VERSION 5.7 ;
  NOWIREEXTENSIONATPIN ON ;
  DIVIDERCHAR "/" ;
  BUSBITCHARS "[]" ;
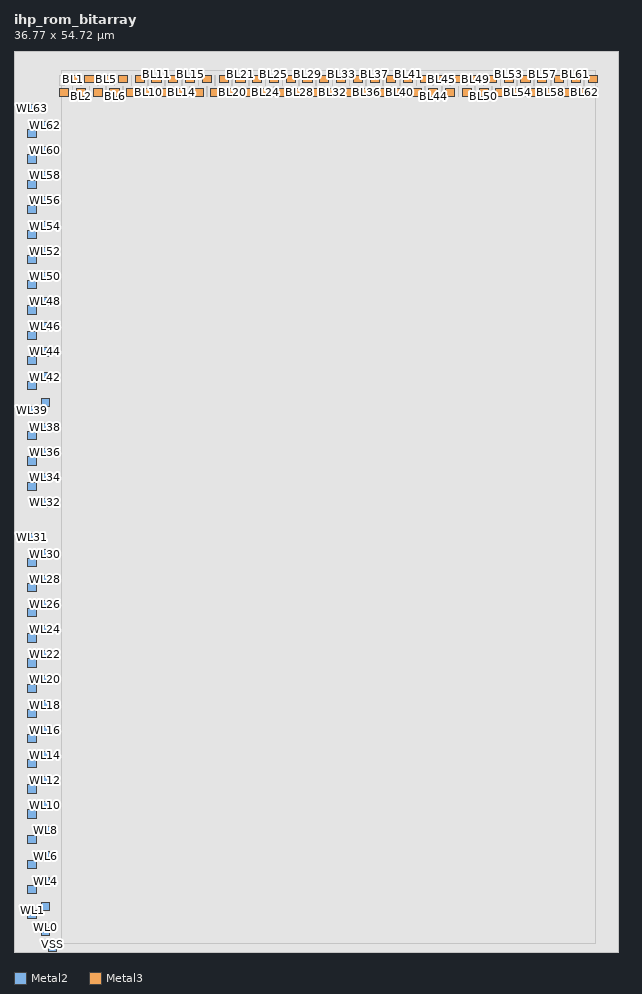
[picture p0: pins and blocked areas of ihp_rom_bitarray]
MACRO ihp_rom_bitarray
  CLASS BLOCK ;
  FOREIGN ihp_rom_bitarray ;
  ORIGIN 2.800 0.990 ;
  SIZE 36.770 BY 54.720 ;
  PIN VSS
    USE GROUND ;
    PORT
      LAYER Metal2 ;
        RECT -0.700 -0.970 -0.200 -0.610 ;
    END
  END VSS
  PIN WL0
    ANTENNAGATEAREA 2.496000 ;
    PORT
      LAYER Metal2 ;
        RECT -1.150 0.005 -0.650 0.505 ;
    END
  END WL0
  PIN WL1
    ANTENNAGATEAREA 2.496000 ;
    PORT
      LAYER Metal2 ;
        RECT -1.950 1.025 -1.450 1.525 ;
    END
  END WL1
  PIN WL2
    ANTENNAGATEAREA 2.496000 ;
    PORT
      LAYER Metal2 ;
        RECT -1.150 1.535 -0.650 2.035 ;
    END
  END WL2
  PIN WL3
    ANTENNAGATEAREA 2.496000 ;
    PORT
      LAYER Metal2 ;
        RECT -1.950 2.555 -1.450 3.055 ;
    END
  END WL3
  PIN WL4
    ANTENNAGATEAREA 2.496000 ;
    PORT
      LAYER Metal2 ;
        RECT -1.150 3.065 -0.650 3.565 ;
    END
  END WL4
  PIN WL5
    ANTENNAGATEAREA 2.496000 ;
    PORT
      LAYER Metal2 ;
        RECT -1.950 4.085 -1.450 4.585 ;
    END
  END WL5
  PIN WL6
    ANTENNAGATEAREA 2.496000 ;
    PORT
      LAYER Metal2 ;
        RECT -1.150 4.595 -0.650 5.095 ;
    END
  END WL6
  PIN WL7
    ANTENNAGATEAREA 2.496000 ;
    PORT
      LAYER Metal2 ;
        RECT -1.950 5.615 -1.450 6.115 ;
    END
  END WL7
  PIN WL8
    ANTENNAGATEAREA 2.496000 ;
    PORT
      LAYER Metal2 ;
        RECT -1.150 6.125 -0.650 6.625 ;
    END
  END WL8
  PIN WL9
    ANTENNAGATEAREA 2.496000 ;
    PORT
      LAYER Metal2 ;
        RECT -1.950 7.145 -1.450 7.645 ;
    END
  END WL9
  PIN WL10
    ANTENNAGATEAREA 2.496000 ;
    PORT
      LAYER Metal2 ;
        RECT -1.150 7.655 -0.650 8.155 ;
    END
  END WL10
  PIN WL11
    ANTENNAGATEAREA 2.496000 ;
    PORT
      LAYER Metal2 ;
        RECT -1.950 8.675 -1.450 9.175 ;
    END
  END WL11
  PIN WL12
    ANTENNAGATEAREA 2.496000 ;
    PORT
      LAYER Metal2 ;
        RECT -1.150 9.185 -0.650 9.685 ;
    END
  END WL12
  PIN WL13
    ANTENNAGATEAREA 2.496000 ;
    PORT
      LAYER Metal2 ;
        RECT -1.950 10.205 -1.450 10.705 ;
    END
  END WL13
  PIN WL14
    ANTENNAGATEAREA 2.496000 ;
    PORT
      LAYER Metal2 ;
        RECT -1.150 10.715 -0.650 11.215 ;
    END
  END WL14
  PIN WL15
    ANTENNAGATEAREA 2.496000 ;
    PORT
      LAYER Metal2 ;
        RECT -1.950 11.735 -1.450 12.235 ;
    END
  END WL15
  PIN WL16
    ANTENNAGATEAREA 2.496000 ;
    PORT
      LAYER Metal2 ;
        RECT -1.150 12.245 -0.650 12.745 ;
    END
  END WL16
  PIN WL17
    ANTENNAGATEAREA 2.496000 ;
    PORT
      LAYER Metal2 ;
        RECT -1.950 13.265 -1.450 13.765 ;
    END
  END WL17
  PIN WL18
    ANTENNAGATEAREA 2.496000 ;
    PORT
      LAYER Metal2 ;
        RECT -1.150 13.775 -0.650 14.275 ;
    END
  END WL18
  PIN WL19
    ANTENNAGATEAREA 2.496000 ;
    PORT
      LAYER Metal2 ;
        RECT -1.950 14.795 -1.450 15.295 ;
    END
  END WL19
  PIN WL20
    ANTENNAGATEAREA 2.496000 ;
    PORT
      LAYER Metal2 ;
        RECT -1.150 15.305 -0.650 15.805 ;
    END
  END WL20
  PIN WL21
    ANTENNAGATEAREA 2.496000 ;
    PORT
      LAYER Metal2 ;
        RECT -1.950 16.325 -1.450 16.825 ;
    END
  END WL21
  PIN WL22
    ANTENNAGATEAREA 2.496000 ;
    PORT
      LAYER Metal2 ;
        RECT -1.150 16.835 -0.650 17.335 ;
    END
  END WL22
  PIN WL23
    ANTENNAGATEAREA 2.496000 ;
    PORT
      LAYER Metal2 ;
        RECT -1.950 17.855 -1.450 18.355 ;
    END
  END WL23
  PIN WL24
    ANTENNAGATEAREA 2.496000 ;
    PORT
      LAYER Metal2 ;
        RECT -1.150 18.365 -0.650 18.865 ;
    END
  END WL24
  PIN WL25
    ANTENNAGATEAREA 2.496000 ;
    PORT
      LAYER Metal2 ;
        RECT -1.950 19.385 -1.450 19.885 ;
    END
  END WL25
  PIN WL26
    ANTENNAGATEAREA 2.496000 ;
    PORT
      LAYER Metal2 ;
        RECT -1.150 19.895 -0.650 20.395 ;
    END
  END WL26
  PIN WL27
    ANTENNAGATEAREA 2.496000 ;
    PORT
      LAYER Metal2 ;
        RECT -1.950 20.915 -1.450 21.415 ;
    END
  END WL27
  PIN WL28
    ANTENNAGATEAREA 2.496000 ;
    PORT
      LAYER Metal2 ;
        RECT -1.150 21.425 -0.650 21.925 ;
    END
  END WL28
  PIN WL29
    ANTENNAGATEAREA 2.496000 ;
    PORT
      LAYER Metal2 ;
        RECT -1.950 22.445 -1.450 22.945 ;
    END
  END WL29
  PIN WL30
    ANTENNAGATEAREA 2.496000 ;
    PORT
      LAYER Metal2 ;
        RECT -1.150 22.955 -0.650 23.455 ;
    END
  END WL30
  PIN WL31
    ANTENNAGATEAREA 2.496000 ;
    PORT
      LAYER Metal2 ;
        RECT -1.950 23.975 -1.450 24.475 ;
    END
  END WL31
  PIN WL32
    ANTENNAGATEAREA 2.496000 ;
    PORT
      LAYER Metal2 ;
        RECT -1.150 26.065 -0.650 26.565 ;
    END
  END WL32
  PIN WL33
    ANTENNAGATEAREA 2.496000 ;
    PORT
      LAYER Metal2 ;
        RECT -1.950 27.085 -1.450 27.585 ;
    END
  END WL33
  PIN WL34
    ANTENNAGATEAREA 2.496000 ;
    PORT
      LAYER Metal2 ;
        RECT -1.150 27.595 -0.650 28.095 ;
    END
  END WL34
  PIN WL35
    ANTENNAGATEAREA 2.496000 ;
    PORT
      LAYER Metal2 ;
        RECT -1.950 28.615 -1.450 29.115 ;
    END
  END WL35
  PIN WL36
    ANTENNAGATEAREA 2.496000 ;
    PORT
      LAYER Metal2 ;
        RECT -1.150 29.125 -0.650 29.625 ;
    END
  END WL36
  PIN WL37
    ANTENNAGATEAREA 2.496000 ;
    PORT
      LAYER Metal2 ;
        RECT -1.950 30.145 -1.450 30.645 ;
    END
  END WL37
  PIN WL38
    ANTENNAGATEAREA 2.496000 ;
    PORT
      LAYER Metal2 ;
        RECT -1.150 30.655 -0.650 31.155 ;
    END
  END WL38
  PIN WL39
    ANTENNAGATEAREA 2.496000 ;
    PORT
      LAYER Metal2 ;
        RECT -1.950 31.675 -1.450 32.175 ;
    END
  END WL39
  PIN WL40
    ANTENNAGATEAREA 2.496000 ;
    PORT
      LAYER Metal2 ;
        RECT -1.150 32.185 -0.650 32.685 ;
    END
  END WL40
  PIN WL41
    ANTENNAGATEAREA 2.496000 ;
    PORT
      LAYER Metal2 ;
        RECT -1.950 33.205 -1.450 33.705 ;
    END
  END WL41
  PIN WL42
    ANTENNAGATEAREA 2.496000 ;
    PORT
      LAYER Metal2 ;
        RECT -1.150 33.715 -0.650 34.215 ;
    END
  END WL42
  PIN WL43
    ANTENNAGATEAREA 2.496000 ;
    PORT
      LAYER Metal2 ;
        RECT -1.950 34.735 -1.450 35.235 ;
    END
  END WL43
  PIN WL44
    ANTENNAGATEAREA 2.496000 ;
    PORT
      LAYER Metal2 ;
        RECT -1.150 35.245 -0.650 35.745 ;
    END
  END WL44
  PIN WL45
    ANTENNAGATEAREA 2.496000 ;
    PORT
      LAYER Metal2 ;
        RECT -1.950 36.265 -1.450 36.765 ;
    END
  END WL45
  PIN WL46
    ANTENNAGATEAREA 2.496000 ;
    PORT
      LAYER Metal2 ;
        RECT -1.150 36.775 -0.650 37.275 ;
    END
  END WL46
  PIN WL47
    ANTENNAGATEAREA 2.496000 ;
    PORT
      LAYER Metal2 ;
        RECT -1.950 37.795 -1.450 38.295 ;
    END
  END WL47
  PIN WL48
    ANTENNAGATEAREA 2.496000 ;
    PORT
      LAYER Metal2 ;
        RECT -1.150 38.305 -0.650 38.805 ;
    END
  END WL48
  PIN WL49
    ANTENNAGATEAREA 2.496000 ;
    PORT
      LAYER Metal2 ;
        RECT -1.950 39.325 -1.450 39.825 ;
    END
  END WL49
  PIN WL50
    ANTENNAGATEAREA 2.496000 ;
    PORT
      LAYER Metal2 ;
        RECT -1.150 39.835 -0.650 40.335 ;
    END
  END WL50
  PIN WL51
    ANTENNAGATEAREA 2.496000 ;
    PORT
      LAYER Metal2 ;
        RECT -1.950 40.855 -1.450 41.355 ;
    END
  END WL51
  PIN WL52
    ANTENNAGATEAREA 2.496000 ;
    PORT
      LAYER Metal2 ;
        RECT -1.150 41.365 -0.650 41.865 ;
    END
  END WL52
  PIN WL53
    ANTENNAGATEAREA 2.496000 ;
    PORT
      LAYER Metal2 ;
        RECT -1.950 42.385 -1.450 42.885 ;
    END
  END WL53
  PIN WL54
    ANTENNAGATEAREA 2.496000 ;
    PORT
      LAYER Metal2 ;
        RECT -1.150 42.895 -0.650 43.395 ;
    END
  END WL54
  PIN WL55
    ANTENNAGATEAREA 2.496000 ;
    PORT
      LAYER Metal2 ;
        RECT -1.950 43.915 -1.450 44.415 ;
    END
  END WL55
  PIN WL56
    ANTENNAGATEAREA 2.496000 ;
    PORT
      LAYER Metal2 ;
        RECT -1.150 44.425 -0.650 44.925 ;
    END
  END WL56
  PIN WL57
    ANTENNAGATEAREA 2.496000 ;
    PORT
      LAYER Metal2 ;
        RECT -1.950 45.445 -1.450 45.945 ;
    END
  END WL57
  PIN WL58
    ANTENNAGATEAREA 2.496000 ;
    PORT
      LAYER Metal2 ;
        RECT -1.150 45.955 -0.650 46.455 ;
    END
  END WL58
  PIN WL59
    ANTENNAGATEAREA 2.496000 ;
    PORT
      LAYER Metal2 ;
        RECT -1.950 46.975 -1.450 47.475 ;
    END
  END WL59
  PIN WL60
    ANTENNAGATEAREA 2.496000 ;
    PORT
      LAYER Metal2 ;
        RECT -1.150 47.485 -0.650 47.985 ;
    END
  END WL60
  PIN WL61
    ANTENNAGATEAREA 2.496000 ;
    PORT
      LAYER Metal2 ;
        RECT -1.950 48.505 -1.450 49.005 ;
    END
  END WL61
  PIN WL62
    ANTENNAGATEAREA 2.496000 ;
    PORT
      LAYER Metal2 ;
        RECT -1.150 49.015 -0.650 49.515 ;
    END
  END WL62
  PIN WL63
    ANTENNAGATEAREA 2.496000 ;
    PORT
      LAYER Metal2 ;
        RECT -1.950 50.035 -1.450 50.535 ;
    END
  END WL63
  PIN BL0
    ANTENNADIFFAREA 3.468000 ;
    PORT
      LAYER Metal3 ;
        RECT -0.025 51.050 0.535 51.510 ;
    END
  END BL0
  PIN BL1
    ANTENNADIFFAREA 3.060000 ;
    PORT
      LAYER Metal3 ;
        RECT 0.485 51.850 1.045 52.310 ;
    END
  END BL1
  PIN BL2
    ANTENNADIFFAREA 3.060000 ;
    PORT
      LAYER Metal3 ;
        RECT 0.995 51.050 1.555 51.510 ;
    END
  END BL2
  PIN BL3
    ANTENNADIFFAREA 3.468000 ;
    PORT
      LAYER Metal3 ;
        RECT 1.505 51.850 2.065 52.310 ;
    END
  END BL3
  PIN BL4
    ANTENNADIFFAREA 3.060000 ;
    PORT
      LAYER Metal3 ;
        RECT 2.015 51.050 2.575 51.510 ;
    END
  END BL4
  PIN BL5
    ANTENNADIFFAREA 3.060000 ;
    PORT
      LAYER Metal3 ;
        RECT 2.525 51.850 3.085 52.310 ;
    END
  END BL5
  PIN BL6
    ANTENNADIFFAREA 3.468000 ;
    PORT
      LAYER Metal3 ;
        RECT 3.035 51.050 3.595 51.510 ;
    END
  END BL6
  PIN BL7
    ANTENNADIFFAREA 3.060000 ;
    PORT
      LAYER Metal3 ;
        RECT 3.545 51.850 4.105 52.310 ;
    END
  END BL7
  PIN BL8
    ANTENNADIFFAREA 3.060000 ;
    PORT
      LAYER Metal3 ;
        RECT 4.055 51.050 4.615 51.510 ;
    END
  END BL8
  PIN BL9
    ANTENNADIFFAREA 3.468000 ;
    PORT
      LAYER Metal3 ;
        RECT 4.565 51.850 5.125 52.310 ;
    END
  END BL9
  PIN BL10
    ANTENNADIFFAREA 3.468000 ;
    PORT
      LAYER Metal3 ;
        RECT 5.075 51.050 5.635 51.510 ;
    END
  END BL10
  PIN BL11
    ANTENNADIFFAREA 3.060000 ;
    PORT
      LAYER Metal3 ;
        RECT 5.585 51.850 6.145 52.310 ;
    END
  END BL11
  PIN BL12
    ANTENNADIFFAREA 3.468000 ;
    PORT
      LAYER Metal3 ;
        RECT 6.095 51.050 6.655 51.510 ;
    END
  END BL12
  PIN BL13
    ANTENNADIFFAREA 3.468000 ;
    PORT
      LAYER Metal3 ;
        RECT 6.605 51.850 7.165 52.310 ;
    END
  END BL13
  PIN BL14
    ANTENNADIFFAREA 3.060000 ;
    PORT
      LAYER Metal3 ;
        RECT 7.115 51.050 7.675 51.510 ;
    END
  END BL14
  PIN BL15
    ANTENNADIFFAREA 3.468000 ;
    PORT
      LAYER Metal3 ;
        RECT 7.625 51.850 8.185 52.310 ;
    END
  END BL15
  PIN BL16
    ANTENNADIFFAREA 3.060000 ;
    PORT
      LAYER Metal3 ;
        RECT 8.135 51.050 8.695 51.510 ;
    END
  END BL16
  PIN BL17
    ANTENNADIFFAREA 3.468000 ;
    PORT
      LAYER Metal3 ;
        RECT 8.645 51.850 9.205 52.310 ;
    END
  END BL17
  PIN BL18
    ANTENNADIFFAREA 3.468000 ;
    PORT
      LAYER Metal3 ;
        RECT 9.155 51.050 9.715 51.510 ;
    END
  END BL18
  PIN BL19
    ANTENNADIFFAREA 3.060000 ;
    PORT
      LAYER Metal3 ;
        RECT 9.665 51.850 10.225 52.310 ;
    END
  END BL19
  PIN BL20
    ANTENNADIFFAREA 3.468000 ;
    PORT
      LAYER Metal3 ;
        RECT 10.175 51.050 10.735 51.510 ;
    END
  END BL20
  PIN BL21
    ANTENNADIFFAREA 3.468000 ;
    PORT
      LAYER Metal3 ;
        RECT 10.685 51.850 11.245 52.310 ;
    END
  END BL21
  PIN BL22
    ANTENNADIFFAREA 3.060000 ;
    PORT
      LAYER Metal3 ;
        RECT 11.195 51.050 11.755 51.510 ;
    END
  END BL22
  PIN BL23
    ANTENNADIFFAREA 3.468000 ;
    PORT
      LAYER Metal3 ;
        RECT 11.705 51.850 12.265 52.310 ;
    END
  END BL23
  PIN BL24
    ANTENNADIFFAREA 3.468000 ;
    PORT
      LAYER Metal3 ;
        RECT 12.215 51.050 12.775 51.510 ;
    END
  END BL24
  PIN BL25
    ANTENNADIFFAREA 3.060000 ;
    PORT
      LAYER Metal3 ;
        RECT 12.725 51.850 13.285 52.310 ;
    END
  END BL25
  PIN BL26
    ANTENNADIFFAREA 3.060000 ;
    PORT
      LAYER Metal3 ;
        RECT 13.235 51.050 13.795 51.510 ;
    END
  END BL26
  PIN BL27
    ANTENNADIFFAREA 3.468000 ;
    PORT
      LAYER Metal3 ;
        RECT 13.745 51.850 14.305 52.310 ;
    END
  END BL27
  PIN BL28
    ANTENNADIFFAREA 3.060000 ;
    PORT
      LAYER Metal3 ;
        RECT 14.255 51.050 14.815 51.510 ;
    END
  END BL28
  PIN BL29
    ANTENNADIFFAREA 3.060000 ;
    PORT
      LAYER Metal3 ;
        RECT 14.765 51.850 15.325 52.310 ;
    END
  END BL29
  PIN BL30
    ANTENNADIFFAREA 3.468000 ;
    PORT
      LAYER Metal3 ;
        RECT 15.275 51.050 15.835 51.510 ;
    END
  END BL30
  PIN BL31
    ANTENNADIFFAREA 3.060000 ;
    PORT
      LAYER Metal3 ;
        RECT 15.785 51.850 16.345 52.310 ;
    END
  END BL31
  PIN BL32
    ANTENNADIFFAREA 3.468000 ;
    PORT
      LAYER Metal3 ;
        RECT 16.295 51.050 16.855 51.510 ;
    END
  END BL32
  PIN BL33
    ANTENNADIFFAREA 3.060000 ;
    PORT
      LAYER Metal3 ;
        RECT 16.805 51.850 17.365 52.310 ;
    END
  END BL33
  PIN BL34
    ANTENNADIFFAREA 3.060000 ;
    PORT
      LAYER Metal3 ;
        RECT 17.315 51.050 17.875 51.510 ;
    END
  END BL34
  PIN BL35
    ANTENNADIFFAREA 3.468000 ;
    PORT
      LAYER Metal3 ;
        RECT 17.825 51.850 18.385 52.310 ;
    END
  END BL35
  PIN BL36
    ANTENNADIFFAREA 3.060000 ;
    PORT
      LAYER Metal3 ;
        RECT 18.335 51.050 18.895 51.510 ;
    END
  END BL36
  PIN BL37
    ANTENNADIFFAREA 3.060000 ;
    PORT
      LAYER Metal3 ;
        RECT 18.845 51.850 19.405 52.310 ;
    END
  END BL37
  PIN BL38
    ANTENNADIFFAREA 3.468000 ;
    PORT
      LAYER Metal3 ;
        RECT 19.355 51.050 19.915 51.510 ;
    END
  END BL38
  PIN BL39
    ANTENNADIFFAREA 3.060000 ;
    PORT
      LAYER Metal3 ;
        RECT 19.865 51.850 20.425 52.310 ;
    END
  END BL39
  PIN BL40
    ANTENNADIFFAREA 3.060000 ;
    PORT
      LAYER Metal3 ;
        RECT 20.375 51.050 20.935 51.510 ;
    END
  END BL40
  PIN BL41
    ANTENNADIFFAREA 3.468000 ;
    PORT
      LAYER Metal3 ;
        RECT 20.885 51.850 21.445 52.310 ;
    END
  END BL41
  PIN BL42
    ANTENNADIFFAREA 3.468000 ;
    PORT
      LAYER Metal3 ;
        RECT 21.395 51.050 21.955 51.510 ;
    END
  END BL42
  PIN BL43
    ANTENNADIFFAREA 3.060000 ;
    PORT
      LAYER Metal3 ;
        RECT 21.905 51.850 22.465 52.310 ;
    END
  END BL43
  PIN BL44
    ANTENNADIFFAREA 3.468000 ;
    PORT
      LAYER Metal3 ;
        RECT 22.415 51.050 22.975 51.510 ;
    END
  END BL44
  PIN BL45
    ANTENNADIFFAREA 3.468000 ;
    PORT
      LAYER Metal3 ;
        RECT 22.925 51.850 23.485 52.310 ;
    END
  END BL45
  PIN BL46
    ANTENNADIFFAREA 3.060000 ;
    PORT
      LAYER Metal3 ;
        RECT 23.435 51.050 23.995 51.510 ;
    END
  END BL46
  PIN BL47
    ANTENNADIFFAREA 3.468000 ;
    PORT
      LAYER Metal3 ;
        RECT 23.945 51.850 24.505 52.310 ;
    END
  END BL47
  PIN BL48
    ANTENNADIFFAREA 3.060000 ;
    PORT
      LAYER Metal3 ;
        RECT 24.455 51.050 25.015 51.510 ;
    END
  END BL48
  PIN BL49
    ANTENNADIFFAREA 3.468000 ;
    PORT
      LAYER Metal3 ;
        RECT 24.965 51.850 25.525 52.310 ;
    END
  END BL49
  PIN BL50
    ANTENNADIFFAREA 3.468000 ;
    PORT
      LAYER Metal3 ;
        RECT 25.475 51.050 26.035 51.510 ;
    END
  END BL50
  PIN BL51
    ANTENNADIFFAREA 3.060000 ;
    PORT
      LAYER Metal3 ;
        RECT 25.985 51.850 26.545 52.310 ;
    END
  END BL51
  PIN BL52
    ANTENNADIFFAREA 3.468000 ;
    PORT
      LAYER Metal3 ;
        RECT 26.495 51.050 27.055 51.510 ;
    END
  END BL52
  PIN BL53
    ANTENNADIFFAREA 3.468000 ;
    PORT
      LAYER Metal3 ;
        RECT 27.005 51.850 27.565 52.310 ;
    END
  END BL53
  PIN BL54
    ANTENNADIFFAREA 3.060000 ;
    PORT
      LAYER Metal3 ;
        RECT 27.515 51.050 28.075 51.510 ;
    END
  END BL54
  PIN BL55
    ANTENNADIFFAREA 3.468000 ;
    PORT
      LAYER Metal3 ;
        RECT 28.025 51.850 28.585 52.310 ;
    END
  END BL55
  PIN BL56
    ANTENNADIFFAREA 3.468000 ;
    PORT
      LAYER Metal3 ;
        RECT 28.535 51.050 29.095 51.510 ;
    END
  END BL56
  PIN BL57
    ANTENNADIFFAREA 3.060000 ;
    PORT
      LAYER Metal3 ;
        RECT 29.045 51.850 29.605 52.310 ;
    END
  END BL57
  PIN BL58
    ANTENNADIFFAREA 3.060000 ;
    PORT
      LAYER Metal3 ;
        RECT 29.555 51.050 30.115 51.510 ;
    END
  END BL58
  PIN BL59
    ANTENNADIFFAREA 3.468000 ;
    PORT
      LAYER Metal3 ;
        RECT 30.065 51.850 30.625 52.310 ;
    END
  END BL59
  PIN BL60
    ANTENNADIFFAREA 3.060000 ;
    PORT
      LAYER Metal3 ;
        RECT 30.575 51.050 31.135 51.510 ;
    END
  END BL60
  PIN BL61
    ANTENNADIFFAREA 3.060000 ;
    PORT
      LAYER Metal3 ;
        RECT 31.085 51.850 31.645 52.310 ;
    END
  END BL61
  PIN BL62
    ANTENNADIFFAREA 3.468000 ;
    PORT
      LAYER Metal3 ;
        RECT 31.595 51.050 32.155 51.510 ;
    END
  END BL62
  PIN BL63
    ANTENNADIFFAREA 3.060000 ;
    PORT
      LAYER Metal3 ;
        RECT 32.105 51.850 32.665 52.310 ;
    END
  END BL63
  OBS
      LAYER GatPoly ;
        RECT -2.800 -0.990 33.970 53.730 ;
      LAYER Metal1 ;
        RECT -2.800 -0.990 33.970 53.730 ;
      LAYER Metal2 ;
        RECT 0.105 -0.490 32.535 52.630 ;
      LAYER Metal3 ;
        RECT -0.045 51.720 0.275 52.330 ;
        RECT 1.255 51.720 1.295 52.330 ;
        RECT 2.275 51.720 2.315 52.330 ;
        RECT 3.295 51.720 3.335 52.330 ;
        RECT 4.315 51.720 4.355 52.330 ;
        RECT 5.335 51.720 5.375 52.330 ;
        RECT 6.355 51.720 6.395 52.330 ;
        RECT 7.375 51.720 7.415 52.330 ;
        RECT 8.395 51.720 8.435 52.330 ;
        RECT 9.415 51.720 9.455 52.330 ;
        RECT 10.435 51.720 10.475 52.330 ;
        RECT 11.455 51.720 11.495 52.330 ;
        RECT 12.475 51.720 12.515 52.330 ;
        RECT 13.495 51.720 13.535 52.330 ;
        RECT 14.515 51.720 14.555 52.330 ;
        RECT 15.535 51.720 15.575 52.330 ;
        RECT 16.555 51.720 16.595 52.330 ;
        RECT 17.575 51.720 17.615 52.330 ;
        RECT 18.595 51.720 18.635 52.330 ;
        RECT 19.615 51.720 19.655 52.330 ;
        RECT 20.635 51.720 20.675 52.330 ;
        RECT 21.655 51.720 21.695 52.330 ;
        RECT 22.675 51.720 22.715 52.330 ;
        RECT 23.695 51.720 23.735 52.330 ;
        RECT 24.715 51.720 24.755 52.330 ;
        RECT 25.735 51.720 25.775 52.330 ;
        RECT 26.755 51.720 26.795 52.330 ;
        RECT 27.775 51.720 27.815 52.330 ;
        RECT 28.795 51.720 28.835 52.330 ;
        RECT 29.815 51.720 29.855 52.330 ;
        RECT 30.835 51.720 30.875 52.330 ;
        RECT 31.855 51.720 31.895 52.330 ;
        RECT 0.745 51.030 0.785 51.640 ;
        RECT 1.765 51.030 1.805 51.640 ;
        RECT 2.785 51.030 2.825 51.640 ;
        RECT 3.805 51.030 3.845 51.640 ;
        RECT 4.825 51.030 4.865 51.640 ;
        RECT 5.845 51.030 5.885 51.640 ;
        RECT 6.865 51.030 6.905 51.640 ;
        RECT 7.885 51.030 7.925 51.640 ;
        RECT 8.905 51.030 8.945 51.640 ;
        RECT 9.925 51.030 9.965 51.640 ;
        RECT 10.945 51.030 10.985 51.640 ;
        RECT 11.965 51.030 12.005 51.640 ;
        RECT 12.985 51.030 13.025 51.640 ;
        RECT 14.005 51.030 14.045 51.640 ;
        RECT 15.025 51.030 15.065 51.640 ;
        RECT 16.045 51.030 16.085 51.640 ;
        RECT 17.065 51.030 17.105 51.640 ;
        RECT 18.085 51.030 18.125 51.640 ;
        RECT 19.105 51.030 19.145 51.640 ;
        RECT 20.125 51.030 20.165 51.640 ;
        RECT 21.145 51.030 21.185 51.640 ;
        RECT 22.165 51.030 22.205 51.640 ;
        RECT 23.185 51.030 23.225 51.640 ;
        RECT 24.205 51.030 24.245 51.640 ;
        RECT 25.225 51.030 25.265 51.640 ;
        RECT 26.245 51.030 26.285 51.640 ;
        RECT 27.265 51.030 27.305 51.640 ;
        RECT 28.285 51.030 28.325 51.640 ;
        RECT 29.305 51.030 29.345 51.640 ;
        RECT 30.325 51.030 30.365 51.640 ;
        RECT 31.345 51.030 31.385 51.640 ;
        RECT 32.365 51.030 32.685 51.640 ;
  END
END ihp_rom_bitarray
END LIBRARY

